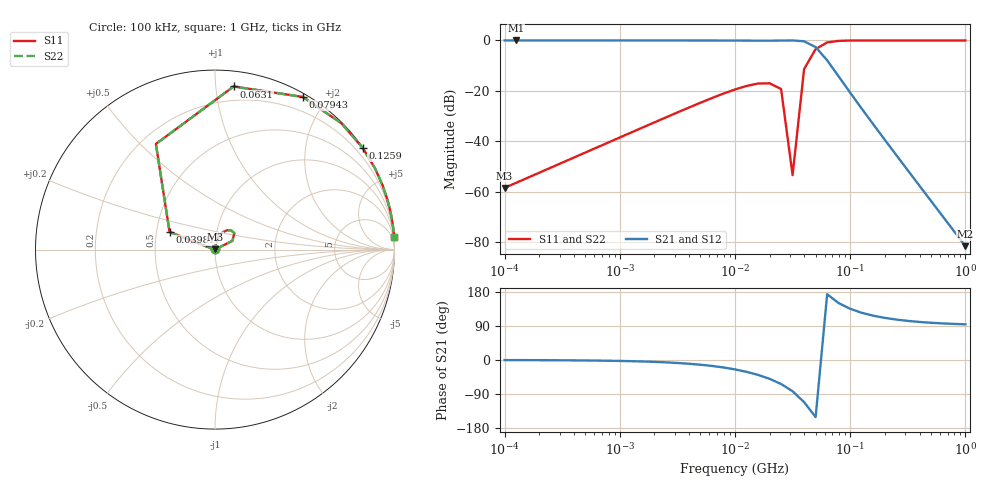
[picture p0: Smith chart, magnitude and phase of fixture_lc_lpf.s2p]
# Hz S MA R 50
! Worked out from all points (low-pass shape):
!   41 points, 100 kHz to 1 GHz, reference 50 ohm
!   highest |S21| = 0.00 dB at 125.9 kHz (marker M1); lowest = -81.6 dB at 1 GHz (marker M2)
!   |S21| within 3 dB of the highest: start of sweep to 51.03 MHz
!   lowest |S11| = -58.5 dB at 100 kHz (marker M3), VSWR 1.00, Z = 50 + j0.119 ohm
!   |S11| at or under -10 dB: start of sweep to 41.53 MHz
!   |S22| runs from -58.5 to 0.0 dB; largest |S21 - S12| = 0
!   S11 on the Smith chart (normalised r, x): 100 kHz: 1.00, +0.00; 39.81 MHz: 0.59, +0.12; 63.1 MHz: 0.10, +1.12; 79.43 MHz: 0.04, +1.73; 125.9 MHz: 0.01, +3.21; 1 GHz: 0, +28
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100000  0.001194 89.8  1 -0.2  1 -0.2  0.001194 89.8
125893  0.001503 89.7  1 -0.3  1 -0.3  0.001503 89.7
501187  0.005982 88.8  1 -1.2  1 -1.2  0.005982 88.8
1258930  0.015 86.9  0.9999 -3.1  0.9999 -3.1  0.015 86.9
2511890  0.02978 83.8  0.9996 -6.2  0.9996 -6.2  0.02978 83.8
5011870  0.05822 77.6  0.9983 -12.4  0.9983 -12.4  0.05822 77.6
1e7  0.1068 65.2  0.9943 -24.8  0.9943 -24.8  0.1068 65.2
1.58489e7  0.14 50.7  0.9901 -39.3  0.9901 -39.3  0.14 50.7
1.99526e7  0.1414 40.4  0.99 -49.6  0.99 -49.6  0.1414 40.4
2.51189e7  0.1089 26.7  0.994 -63.3  0.994 -63.3  0.1089 26.7
3.16228e7  0.002137 -172.4  1 -82.4  1 -82.4  0.002137 -172.4
3.98107e7  0.2716 158.8  0.9624 -111.2  0.9624 -111.2  0.2716 158.8
5.01187e7  0.6743 119.2  0.7385 -150.8  0.7385 -150.8  0.6743 119.2
6.30957e7  0.9146 83.5  0.4043 173.5  0.4043 173.5  0.9146 83.5
7.94328e7  0.9811 60.1  0.1936 150.1  0.1936 150.1  0.9811 60.1
1e8  0.9958 45.1  0.0921 135.1  0.0921 135.1  0.9958 45.1
1.25893e8  0.999 34.6  0.0445 124.6  0.0445 124.6  0.999 34.6
1.58489e8  0.9998 27.0  0.02178 117.0  0.02178 117.0  0.9998 27.0
2.51189e8  1 16.7  0.00534 106.7  0.00534 106.7  1 16.7
3.98107e8  1 10.5  0.001328 100.5  0.001328 100.5  1 10.5
7.94328e8  1 5.2  0.0001665 95.2  0.0001665 95.2  1 5.2
1e9  1 4.1  8.338e-05 94.1  8.338e-05 94.1  1 4.1
